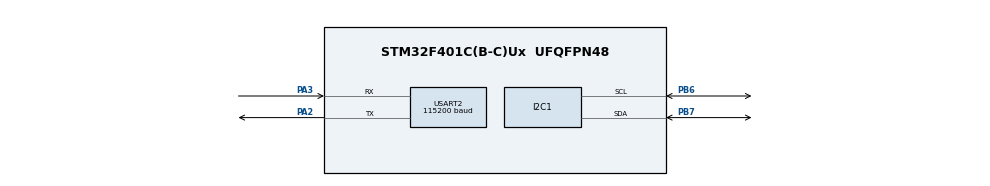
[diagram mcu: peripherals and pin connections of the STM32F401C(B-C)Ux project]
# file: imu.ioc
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Mcu.Family=STM32F4
Mcu.Name=STM32F401C(B-C)Ux
Mcu.Package=UFQFPN48
NVIC.PriorityGroup=NVIC_PRIORITYGROUP_4
PA2.Mode=Asynchronous
PA2.Signal=USART2_TX
PA3.Mode=Asynchronous
PA3.Signal=USART2_RX
PB6.Mode=I2C
PB6.Signal=I2C1_SCL
PB7.Mode=I2C
PB7.Signal=I2C1_SDA
PH0\ -\ OSC_IN.Mode=HSE-External-Oscillator
PH0\ -\ OSC_IN.Signal=RCC_OSC_IN
PH1\ -\ OSC_OUT.Mode=HSE-External-Oscillator
PH1\ -\ OSC_OUT.Signal=RCC_OSC_OUT
ProjectManager.HeapSize=0x200
ProjectManager.StackSize=0x400
ProjectManager.TargetToolchain=STM32CubeIDE
RCC.48MHZClocksFreq_Value=42000000
RCC.AHBFreq_Value=84000000
RCC.APB1CLKDivider=RCC_HCLK_DIV2
RCC.APB1Freq_Value=42000000
RCC.APB1TimFreq_Value=84000000
RCC.APB2Freq_Value=84000000
RCC.APB2TimFreq_Value=84000000
RCC.CortexFreq_Value=84000000
RCC.HCLKFreq_Value=84000000
RCC.HSE_VALUE=25000000
RCC.HSI_VALUE=16000000
RCC.LSE_VALUE=32768
RCC.PLLM=25
RCC.PLLN=168
RCC.PLLSourceVirtual=RCC_PLLSOURCE_HSE
RCC.SYSCLKFreq_VALUE=84000000
RCC.SYSCLKSource=RCC_SYSCLKSOURCE_PLLCLK
RCC.VCOOutputFreq_Value=168000000
USART2.BaudRate=115200
USART2.VirtualMode=VM_ASYNC
board=custom

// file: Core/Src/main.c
/* USER CODE BEGIN Header */
/**
  ******************************************************************************
  * @file           : main.c
  * @brief          : Main program body
  ******************************************************************************
  * @attention
  *
  * Copyright (c) 2026 STMicroelectronics.
  * All rights reserved.
  *
  * This software is licensed under terms that can be found in the LICENSE file
  * in the root directory of this software component.
  * If no LICENSE file comes with this software, it is provided AS-IS.
  *
  ******************************************************************************
  */
/* USER CODE END Header */
#include "main.h"

/* USER CODE BEGIN Includes */
#include <stdio.h>
#include <string.h>
/* USER CODE END Includes */

I2C_HandleTypeDef hi2c1;

UART_HandleTypeDef huart2;

/* USER CODE BEGIN PV */
#define MPU6050_ADDR 0xD0
uint8_t rec_data[14];                   // Menampung 14 byte data mentah lengkap
int16_t accel_x, accel_y, accel_z;
int16_t raw_temp;                       // [BARU] Menampung data mentah suhu dari sensor
int16_t gyro_x, gyro_y, gyro_z;
char uart_buf[120];                     // Diperbesar agar muat string 7 variabel
/* USER CODE END PV */

void SystemClock_Config(void);
static void MX_GPIO_Init(void);
static void MX_I2C1_Init(void);
static void MX_USART2_UART_Init(void);

int main(void)
{

  /* MCU Configuration--------------------------------------------------------*/

  /* Reset of all peripherals, Initializes the Flash interface and the Systick. */
  HAL_Init();

  /* Configure the system clock */
  SystemClock_Config();

  /* Initialize all configured peripherals */
  MX_GPIO_Init();
  MX_I2C1_Init();
  MX_USART2_UART_Init();
  /* USER CODE BEGIN 2 */
  uint8_t Data = 0;
    if (HAL_I2C_IsDeviceReady(&hi2c1, MPU6050_ADDR, 1, 1000) == HAL_OK) {
        char *msg = "MPU6050 Siap!\r\n";
        HAL_UART_Transmit(&huart2, (uint8_t *)msg, strlen(msg), 1000);
    }

    // Membangunkan MPU6050 dari mode sleep
    HAL_I2C_Mem_Write(&hi2c1, MPU6050_ADDR, 0x6B, 1, &Data, 1, 1000);
    HAL_Delay(100);
  /* USER CODE END 2 */

  /* Infinite loop */
  while (1)
  {

    /* USER CODE BEGIN 3 */
    // Membaca 14 byte sekaligus dari register awal 0x3B
    HAL_I2C_Mem_Read(&hi2c1, MPU6050_ADDR, 0x3B, 1, rec_data, 14, 1000);

    // 1. Konversi Data Akselerometer (Byte 0 - 5)
    accel_x = (int16_t)(rec_data[0] << 8 | rec_data[1]);
    accel_y = (int16_t)(rec_data[2] << 8 | rec_data[3]);
    accel_z = (int16_t)(rec_data[4] << 8 | rec_data[5]);

    // 2. [BARU] Konversi Data Suhu (Byte 6 - 7)
    raw_temp = (int16_t)(rec_data[6] << 8 | rec_data[7]);

    // 3. Konversi Data Giroskop (Byte 8 - 13)
    gyro_x = (int16_t)(rec_data[8] << 8 | rec_data[9]);
    gyro_y = (int16_t)(rec_data[10] << 8 | rec_data[11]);
    gyro_z = (int16_t)(rec_data[12] << 8 | rec_data[13]);

    // Menggabungkan 7 variabel menjadi format CSV (ditambah %d untuk raw_temp)
    sprintf(uart_buf, "%d,%d,%d,%d,%d,%d,%d\r\n", accel_x, accel_y, accel_z, raw_temp, gyro_x, gyro_y, gyro_z);
    HAL_UART_Transmit(&huart2, (uint8_t *)uart_buf, strlen(uart_buf), 1000);

    HAL_Delay(50);
  }
  /* USER CODE END 3 */
}

void SystemClock_Config(void)
{
  RCC_OscInitTypeDef RCC_OscInitStruct = {0};
  RCC_ClkInitTypeDef RCC_ClkInitStruct = {0};

  /** Configure the main internal regulator output voltage
  */
  __HAL_RCC_PWR_CLK_ENABLE();
  __HAL_PWR_VOLTAGESCALING_CONFIG(PWR_REGULATOR_VOLTAGE_SCALE2);

  /** Initializes the RCC Oscillators according to the specified parameters
  * in the RCC_OscInitTypeDef structure.
  */
  RCC_OscInitStruct.OscillatorType = RCC_OSCILLATORTYPE_HSI;
  RCC_OscInitStruct.HSIState = RCC_HSI_ON;
  RCC_OscInitStruct.HSICalibrationValue = RCC_HSICALIBRATION_DEFAULT;
  RCC_OscInitStruct.PLL.PLLState = RCC_PLL_NONE;
  if (HAL_RCC_OscConfig(&RCC_OscInitStruct) != HAL_OK)
  {
    Error_Handler();
  }

  /** Initializes the CPU, AHB and APB buses clocks
  */
  RCC_ClkInitStruct.ClockType = RCC_CLOCKTYPE_HCLK|RCC_CLOCKTYPE_SYSCLK
                              |RCC_CLOCKTYPE_PCLK1|RCC_CLOCKTYPE_PCLK2;
  RCC_ClkInitStruct.SYSCLKSource = RCC_SYSCLKSOURCE_HSI;
  RCC_ClkInitStruct.AHBCLKDivider = RCC_SYSCLK_DIV1;
  RCC_ClkInitStruct.APB1CLKDivider = RCC_HCLK_DIV1;
  RCC_ClkInitStruct.APB2CLKDivider = RCC_HCLK_DIV1;

  if (HAL_RCC_ClockConfig(&RCC_ClkInitStruct, FLASH_LATENCY_0) != HAL_OK)
  {
    Error_Handler();
  }
}

static void MX_I2C1_Init(void)
{

  hi2c1.Instance = I2C1;
  hi2c1.Init.ClockSpeed = 100000;
  hi2c1.Init.DutyCycle = I2C_DUTYCYCLE_2;
  hi2c1.Init.OwnAddress1 = 0;
  hi2c1.Init.AddressingMode = I2C_ADDRESSINGMODE_7BIT;
  hi2c1.Init.DualAddressMode = I2C_DUALADDRESS_DISABLE;
  hi2c1.Init.OwnAddress2 = 0;
  hi2c1.Init.GeneralCallMode = I2C_GENERALCALL_DISABLE;
  hi2c1.Init.NoStretchMode = I2C_NOSTRETCH_DISABLE;
  if (HAL_I2C_Init(&hi2c1) != HAL_OK)
  {
    Error_Handler();
  }

}

static void MX_USART2_UART_Init(void)
{

  huart2.Instance = USART2;
  huart2.Init.BaudRate = 115200;
  huart2.Init.WordLength = UART_WORDLENGTH_8B;
  huart2.Init.StopBits = UART_STOPBITS_1;
  huart2.Init.Parity = UART_PARITY_NONE;
  huart2.Init.Mode = UART_MODE_TX_RX;
  huart2.Init.HwFlowCtl = UART_HWCONTROL_NONE;
  huart2.Init.OverSampling = UART_OVERSAMPLING_16;
  if (HAL_UART_Init(&huart2) != HAL_OK)
  {
    Error_Handler();
  }

}

static void MX_GPIO_Init(void)
{

  /* GPIO Ports Clock Enable */
  __HAL_RCC_GPIOA_CLK_ENABLE();
  __HAL_RCC_GPIOB_CLK_ENABLE();

}

void Error_Handler(void)
{
  __disable_irq();
  while (1)
  {
  }
}
